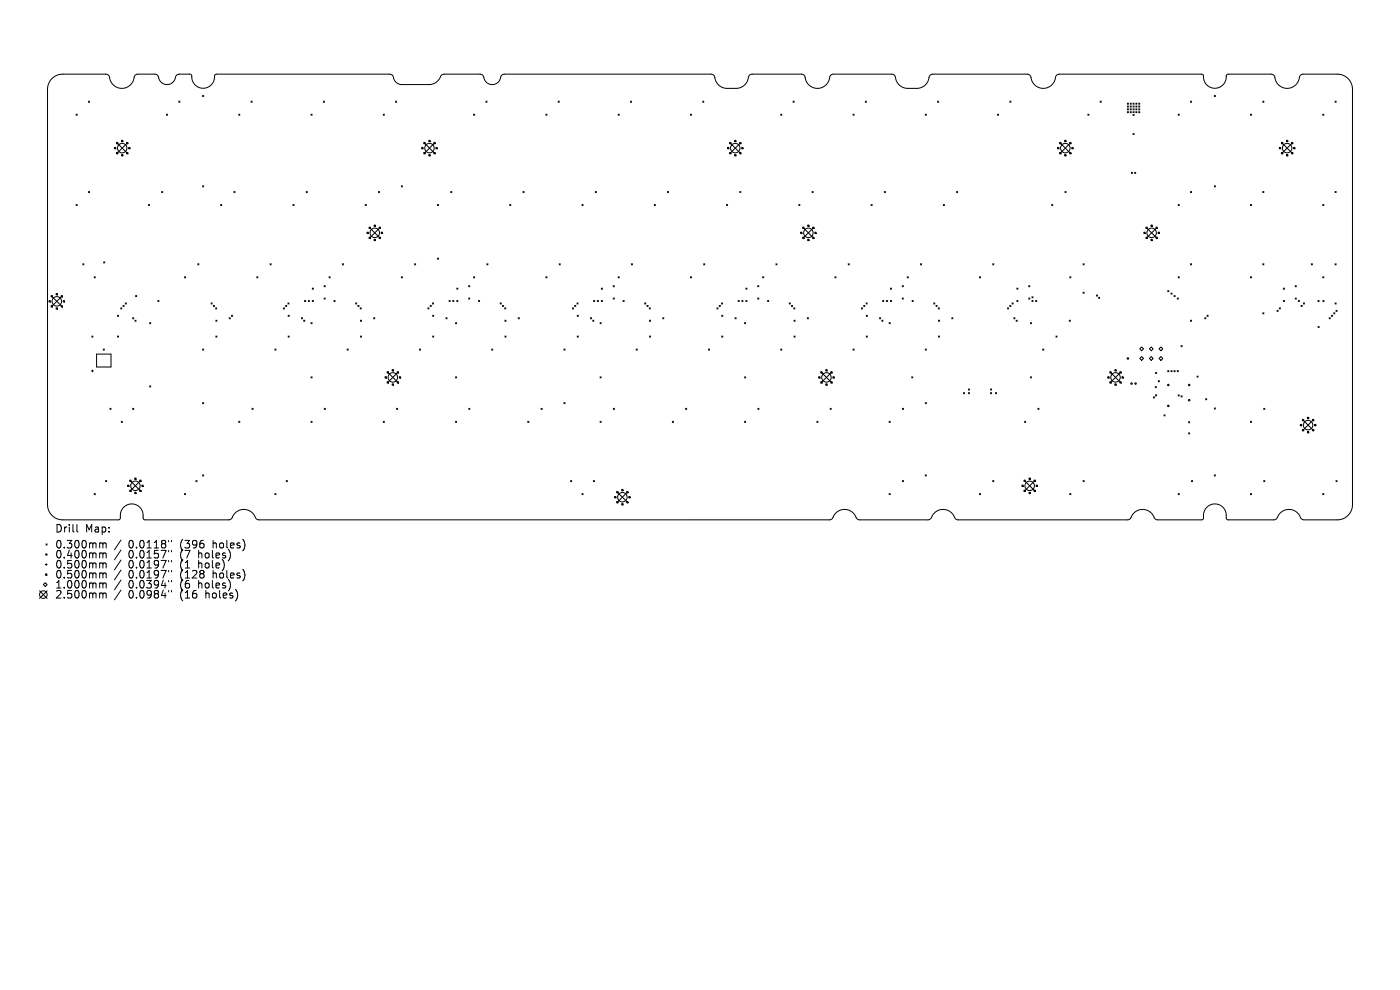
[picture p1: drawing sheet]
<svg xmlns="http://www.w3.org/2000/svg" width="297mm" height="210mm" viewBox="0 0 297 210" stroke-linecap="round" stroke-linejoin="round" font-family="sans-serif">
<defs><g id="words">
<g font-size="2.2">
<text x="11.6" y="113.2">Drill</text>
<text x="18.1" y="113.2">Map:</text>
<text x="11.6" y="116.6">0.300mm</text>
<text x="11.6" y="118.7">0.400mm</text>
<text x="27.3" y="116.6">0.0118&quot;</text>
<text x="27.3" y="118.7">0.0157&quot;</text>
<text x="38.3" y="116.6">(396</text>
<text x="38.3" y="118.7">(7</text>
<text x="42.3" y="118.7">holes)</text>
<text x="45.4" y="116.6">holes)</text>
<text x="11.6" y="120.8">0.500mm</text>
<text x="11.6" y="122.9">0.500mm</text>
<text x="11.6" y="125.1">1.000mm</text>
<text x="27.3" y="120.8">0.0197&quot;</text>
<text x="27.3" y="122.9">0.0197&quot;</text>
<text x="27.3" y="125.1">0.0394&quot;</text>
<text x="38.3" y="120.8">(1</text>
<text x="38.3" y="122.9">(128</text>
<text x="38.3" y="125.1">(6</text>
<text x="42.3" y="120.8">hole)</text>
<text x="42.3" y="125.1">holes)</text>
<text x="45.4" y="122.9">holes)</text>
<text x="11.6" y="127.2">2.500mm</text>
<text x="27.3" y="127.2">0.0984&quot;</text>
<text x="38.3" y="127.2">(16</text>
<text x="43.8" y="127.2">holes)</text>
</g>
</g></defs>
<g fill="none" stroke="#000" stroke-width=".21">
<path d="M11.1 16.6a3.2 3.2 0 0 1 2.3-.9h9.1a.81 .81 0 0 1 .8 .7 2.66 2.66 0 0 0 2.7 2.3 2.66 2.66 0 0 0 2.5-2.6l.7-.4h3.7a1.03 1.03 0 0 1 .9 1.2 1.89 1.89 0 0 0 2.1 1 1.89 1.89 0 0 0 1.5-1.8l.6-.4h2.3l.3 .2a2.5 2.5 0 0 0 2.5 2.8 2.5 2.5 0 0 0 2.5-2.8l.3-.2h36.8a1.03 1.03 0 0 1 .9 1.2l.6 .7 .9 .3h6.1a3.5 3.5 0 0 0 2.6-2l.4-.2h7.6a1.03 1.03 0 0 1 1 1.2 1.88 1.88 0 0 0 2.1 1 1.88 1.88 0 0 0 1.4-1.8l.7-.4h43.8a.81 .81 0 0 1 .8 .7 2.62 2.62 0 0 0 2.6 2.3h2.2a2.94 2.94 0 0 0 2.5-2.6l.7-.4h10.4a.8 .8 0 0 1 .8 .7 2.66 2.66 0 0 0 2.8 2.3 2.66 2.66 0 0 0 2.5-2.6l.3-.3 .4-.1h12.4a.8 .8 0 0 1 .8 .7 2.62 2.62 0 0 0 2.6 2.3h2.1a2.94 2.94 0 0 0 2.5-2.6l.7-.4h20a.8 .8 0 0 1 .8 .7 2.66 2.66 0 0 0 2.8 2.3 2.66 2.66 0 0 0 2.5-2.6l.3-.3 .4-.1h30.2l.4 .2a2.5 2.5 0 0 0 2.5 2.8 2.5 2.5 0 0 0 2.4-2.8l.3-.2h9.2a.81 .81 0 0 1 .8 .7 2.67 2.67 0 0 0 2.8 2.3 2.67 2.67 0 0 0 2.5-2.6l.6-.4h7.3a3.2 3.2 0 0 1 3.2 3.2v88.2a3.2 3.2 0 0 1-3.2 3.2h-7.1l-.5-.3a2.74 2.74 0 0 0-2.7-1.9 2.74 2.74 0 0 0-2.6 1.9l-.6 .3h-9.7l-.2-.1-.2-.3a2.48 2.48 0 0 0-3-2.9 2.53 2.53 0 0 0-1.8 2.9l-.1 .3-.3 .1h-9.3l-.6-.3a2.74 2.74 0 0 0-2.6-1.9 2.74 2.74 0 0 0-2.6 1.9l-.6 .3h-35.9l-.6-.2a2.86 2.86 0 0 0-3.8-1.8l-.9 .7-.6 1-.5 .3h-14.5l-.5-.2a2.86 2.86 0 0 0-3.9-1.8l-.9 .7-.6 1-.5 .3h-121.1l-.5-.2a2.86 2.86 0 0 0-3.8-1.8l-.9 .7-.6 1-.5 .3h-17.8l-.3-.1-.1-.3a2.48 2.48 0 0 0-3.1-2.9 2.53 2.53 0 0 0-1.8 2.9l-.1 .3-.3 .1h-11.8a3.2 3.2 0 0 1-3.2-3.2v-88.2a3.2 3.2 0 0 1 1-2.3zM16.1 24.2l.3 .3M16.4 24.2l-.3 .3M18.8 21.5l.2 .2M19 21.5l-.2 .2M24.3 31.3h.3v.3h-.3zM24.7 30.2h.3v.3h-.3zM24.7 32.3h.3v.3h-.3zM24.9 30.4l2 2M25.8 29.8h.3v.3h-.3zM25.8 32.8h.3v.3h-.3zM26.8 30.2h.3v.3h-.3z"/>
<path d="M26.8 32.3h.3v.3h-.3zM26.9 30.4l-2 2M27.3 31.3h.3v.3h-.3zM35.3 24.2l.3 .3M35.6 24.2l-.3 .3M37.9 21.5l.3 .2M38.2 21.5l-.3 .2M43 20.2l.2 .3M43 39.4l.2 .3M43.2 20.2l-.2 .3M43.2 39.4l-.2 .3M50.6 24.2l.3 .3"/>
<path d="M50.9 24.2l-.3 .3M53.3 21.5l.2 .2M53.5 21.5l-.2 .2M66 24.2l.2 .3M66.2 24.2l-.2 .3M68.6 21.5l.2 .2M68.8 21.5l-.2 .2M81.3 24.2l.2 .3M81.5 24.2l-.2 .3M83.9 21.5l.3 .2M84.2 21.5l-.3 .2M85.1 39.4l.3 .3"/>
<path d="M85.4 39.4l-.3 .3M89.5 31.3h.2v.3h-.2zM89.9 30.2h.3v.3h-.3zM89.9 32.3h.3v.3h-.3zM90.1 30.4l2 2M91 29.8h.3v.3h-.3zM91 32.8h.3v.3h-.3zM92 30.2h.3v.3h-.3zM92 32.3h.3v.3h-.3zM92.1 30.4l-2 2M92.5 31.3h.3v.3h-.3zM100.5 24.2l.2 .3"/>
<path d="M100.7 24.2l-.2 .3M103.1 21.5l.2 .2M103.3 21.5l-.2 .2M115.8 24.2l.2 .3M116 24.2l-.2 .3M118.4 21.5l.3 .2M118.7 21.5l-.3 .2M131.1 24.2l.3 .3M131.4 24.2l-.3 .3M133.7 21.5l.3 .2M134 21.5l-.3 .2M146.5 24.2l.2 .3"/>
<path d="M146.7 24.2l-.2 .3M149.1 21.5l.2 .2M149.3 21.5l-.2 .2M154.3 31.3h.3v.3h-.3zM154.8 30.2h.3v.3h-.3zM154.8 32.3h.3v.3h-.3zM155 30.4l2 2M155.8 29.8h.3v.3h-.3zM155.8 32.8h.3v.3h-.3zM156.9 30.2h.3v.3h-.3zM156.9 32.3h.3v.3h-.3zM157 30.4l-2 2"/>
<path d="M157.4 31.3h.2v.3h-.2zM165.6 24.2l.3 .3M165.9 24.2l-.3 .3M168.2 21.5l.3 .2M168.5 21.5l-.3 .2M181 24.2l.2 .3M181.2 24.2l-.2 .3M183.6 21.5l.2 .2M183.8 21.5l-.2 .2M196.3 24.2l.2 .3M196.5 24.2l-.2 .3M198.9 21.5l.2 .2"/>
<path d="M199.1 21.5l-.2 .2M211.6 24.2l.3 .3M211.9 24.2l-.3 .3M214.2 21.5l.3 .2M214.5 21.5l-.3 .2M224.3 31.3h.3v.3h-.3zM224.8 30.2h.3v.3h-.3zM224.8 32.3h.3v.3h-.3zM225 30.4l2 2M225.9 29.8h.2v.3h-.2zM225.9 32.8h.2v.3h-.2zM226.9 30.2h.3v.3h-.3z"/>
<path d="M226.9 32.3h.3v.3h-.3zM227 30.4l-2 2M227.4 31.3h.3v.3h-.3zM230.8 24.2l.2 .3M231 24.2l-.2 .3M233.4 21.5l.2 .2M233.6 21.5l-.2 .2M239.2 21.9l.2 .2M239.2 22.5l.2 .2M239.2 23.1l.2 .2M239.2 23.7l.2 .2M239.4 21.9l-.2 .2"/>
<path d="M239.4 22.5l-.2 .2M239.4 23.1l-.2 .2M239.4 23.7l-.2 .2M239.8 22.5l.2 .2M239.8 23.1l.2 .2M239.8 23.7l.2 .2M239.8 21.9l.2 .2M240 21.9l-.2 .2M240 22.5l-.2 .2M240 23.1l-.2 .2M240 23.7l-.2 .2M240 36.5l.3 .3"/>
<path d="M240.3 36.5l-.3 .3M240.4 23.1l.2 .2M240.4 23.7l.2 .2M240.4 24.3l.2 .2M240.4 22.5l.2 .2M240.4 21.9l.2 .2M240.4 28.3l.2 .3M240.6 21.9l-.2 .2M240.6 22.5l-.2 .2M240.6 23.1l-.2 .2M240.6 23.7l-.2 .2M240.6 24.3l-.2 .2"/>
<path d="M240.6 28.3l-.2 .3M240.7 36.5l.2 .3M240.9 36.5l-.2 .3M241 23.7l.2 .2M241 23.1l.2 .2M241 22.5l.2 .2M241 21.9l.2 .2M241.2 21.9l-.2 .2M241.2 22.5l-.2 .2M241.2 23.1l-.2 .2M241.2 23.7l-.2 .2M241.6 23.7l.2 .2"/>
<path d="M241.6 23.1l.2 .2M241.6 22.5l.2 .2M241.6 21.9l.2 .2M241.8 21.9l-.2 .2M241.8 22.5l-.2 .2M241.8 23.1l-.2 .2M241.8 23.7l-.2 .2M249.9 24.2l.3 .3M250.2 24.2l-.3 .3M252.6 21.5l.2 .2M252.8 21.5l-.2 .2M257.6 20.2l.2 .3"/>
<path d="M257.6 39.4l.2 .3M257.8 20.2l-.2 .3M257.8 39.4l-.2 .3M265.3 24.2l.2 .3M265.5 24.2l-.2 .3M267.9 21.5l.2 .2M268.1 21.5l-.2 .2M271.4 31.3h.3v.3h-.3zM271.8 30.2h.3v.3h-.3zM271.8 32.3h.3v.3h-.3zM272.1 30.4l2 2M272.9 29.8h.3v.3h-.3z"/>
<path d="M272.9 32.8h.3v.3h-.3zM274 30.2h.3v.3h-.3zM274 32.3h.3v.3h-.3zM274.1 30.4l-2 2M274.4 31.3h.3v.3h-.3zM280.6 24.2l.2 .3M280.8 24.2l-.2 .3M283.2 21.5l.3 .2M283.5 21.5l-.3 .2M16.1 43.4l.3 .2M16.4 43.4l-.3 .2M17.6 56l.2 .2"/>
<path d="M17.8 56l-.2 .2M18.8 40.6l.2 .3M19 40.6l-.2 .3M20 58.7l.2 .2M20.2 58.7l-.2 .2M22 55.5l.2 .3M22.2 55.5l-.2 .3M31.5 43.4l.2 .2M31.7 43.4l-.2 .2M34.3 40.6l.2 .3M34.5 40.6l-.2 .3M39.1 58.7l.3 .2"/>
<path d="M39.4 58.7l-.3 .2M42 56l.2 .2M42.2 56l-.2 .2M46.8 43.4l.2 .2M47 43.4l-.2 .2M49.6 40.6l.3 .3M49.9 40.6l-.3 .3M54.5 58.7l.2 .2M54.7 58.7l-.2 .2M57.3 56l.2 .2M57.5 56l-.2 .2M62.1 43.4l.3 .2"/>
<path d="M62.4 43.4l-.3 .2M65 40.6l.2 .3M65.2 40.6l-.2 .3M69.8 58.7l.2 .2M70 58.7l-.2 .2M72.6 56l.3 .2M72.9 56l-.3 .2M77.5 43.4l.2 .2M77.7 43.4l-.2 .2M77.9 49.3h.2v.2h-.2zM78.3 48.2h.3v.3h-.3zM78.3 50.3h.3v.3h-.3z"/>
<path d="M78.5 48.4l2 2M79.4 47.7h.2v.3h-.2zM79.4 50.8h.2v.2h-.2zM80.3 40.6l.2 .3M80.4 48.2h.3v.3h-.3zM80.4 50.3h.3v.3h-.3zM80.5 48.4l-2 2M80.5 40.6l-.2 .3M80.9 49.3h.3v.2h-.3zM85.1 58.7l.3 .2M85.4 58.7l-.3 .2M88 56l.2 .2"/>
<path d="M88.2 56l-.2 .2M92.8 43.4l.2 .2M92.8 54.7l.2 .3M93 43.4l-.2 .2M93 54.7l-.2 .3M95.6 40.6l.3 .3M95.9 40.6l-.3 .3M100.5 58.7l.2 .2M100.7 58.7l-.2 .2M103.3 56l.2 .2M103.5 56l-.2 .2M108.1 43.4l.3 .2"/>
<path d="M108.4 43.4l-.3 .2M110.9 40.6l.3 .3M111.2 40.6l-.3 .3M115.8 58.7l.2 .2M116 58.7l-.2 .2M118.6 56l.3 .2M118.9 56l-.3 .2M123.5 43.4l.2 .2M123.7 43.4l-.2 .2M126.3 40.6l.2 .3M126.5 40.6l-.2 .3M131.1 58.7l.3 .2"/>
<path d="M131.4 58.7l-.3 .2M133.9 56l.3 .2M134.2 56l-.3 .2M138.8 43.4l.2 .2M139 43.4l-.2 .2M141.6 40.6l.3 .3M141.9 40.6l-.3 .3M146.5 58.7l.2 .2M146.7 58.7l-.2 .2M149.3 56l.2 .2M149.5 56l-.2 .2M154.1 43.4l.3 .2"/>
<path d="M154.4 43.4l-.3 .2M156.9 40.6l.3 .3M157.2 40.6l-.3 .3M161.8 58.7l.2 .2M162 58.7l-.2 .2M164.6 56l.2 .2M164.8 56l-.2 .2M169.5 43.4l.2 .2M169.7 43.4l-.2 .2M169.8 49.3h.3v.2h-.3zM170.3 48.2h.3v.3h-.3zM170.3 50.3h.3v.3h-.3z"/>
<path d="M170.5 48.4l2 2M171.3 47.7h.3v.3h-.3zM171.3 50.8h.3v.2h-.3zM172.3 40.6l.2 .3M172.4 48.2h.3v.3h-.3zM172.4 50.3h.3v.3h-.3zM172.5 48.4l-2 2M172.5 40.6l-.2 .3M172.9 49.3h.2v.2h-.2zM177.1 58.7l.3 .2M177.4 58.7l-.3 .2M179.9 56l.3 .2"/>
<path d="M180.2 56l-.3 .2M184.8 43.4l.2 .2M185 43.4l-.2 .2M187.6 40.6l.2 .3M187.8 40.6l-.2 .3M192.5 58.7l.2 .2M192.7 58.7l-.2 .2M195.3 56l.2 .2M195.5 56l-.2 .2M200.1 43.4l.3 .2M200.4 43.4l-.3 .2M202.9 40.6l.3 .3"/>
<path d="M203.2 40.6l-.3 .3M207.8 58.7l.2 .2M208 58.7l-.2 .2M210.6 56l.2 .2M210.8 56l-.2 .2M223.1 43.4l.3 .2M223.4 43.4l-.3 .2M225.9 40.6l.3 .3M226.2 40.6l-.3 .3M226.9 58.7l.3 .2M227.2 58.7l-.3 .2M229.8 56l.2 .2"/>
<path d="M230 56l-.2 .2M242.7 49.3h.2v.2h-.2zM243.1 48.2h.3v.3h-.3zM243.1 50.3h.3v.3h-.3zM243.3 48.4l2 2M244.2 47.7h.3v.3h-.3zM244.2 50.8h.3v.2h-.3zM245.2 48.2h.3v.3h-.3zM245.2 50.3h.3v.3h-.3zM245.3 48.4l-2 2M245.7 49.3h.3v.2h-.3zM249.9 43.4l.3 .2"/>
<path d="M249.9 58.7l.3 .2M250.2 43.4l-.3 .2M250.2 58.7l-.3 .2M252.6 40.6l.2 .3M252.6 56l.2 .2M252.8 40.6l-.2 .3M252.8 56l-.2 .2M265.3 43.4l.2 .2M265.3 58.7l.2 .2M265.5 43.4l-.2 .2M265.5 58.7l-.2 .2M267.9 56l.2 .2"/>
<path d="M267.9 40.6l.2 .3M268.1 56l-.2 .2M268.1 40.6l-.2 .3M278.2 56l.2 .2M278.4 56l-.2 .2M280.6 43.4l.2 .2M280.6 58.7l.2 .2M280.8 43.4l-.2 .2M280.8 58.7l-.2 .2M283.2 56l.3 .2M283.2 40.6l.3 .3M283.5 40.6l-.3 .3"/>
<path d="M283.5 56l-.3 .2M10.4 63.8h.3v.3h-.3zM10.8 62.7h.3v.3h-.3zM10.8 64.8h.3v.3h-.3zM11 62.9l2.1 2M11.9 62.3h.3v.3h-.3zM11.9 65.3h.3v.3h-.3zM13 62.7h.3v.3h-.3zM13 64.8h.3v.3h-.3zM13.1 62.9l-2.1 2M13.4 63.8h.3v.3h-.3zM19.4 78.7h.4"/>
<path d="M19.5 71.3l.2 .2M19.6 78.5v.4M19.7 71.3l-.2 .2M20.5 75.1h3v2.7h-3zM21.9 74l.2 .3M22.1 74l-.2 .3M24.9 66.9l.3 .2M24.9 71.3l.3 .2M25.2 66.9l-.3 .2M25.2 71.3l-.3 .2M25.6 65.3l.3 .2M25.9 65.3l-.3 .2"/>
<path d="M26.1 64.8l.2 .2M26.3 64.8l-.2 .2M26.6 64.3l.2 .2M26.8 64.3l-.2 .2M28.1 67.4l.3 .2M28.4 67.4l-.3 .2M28.6 67.9l.3 .3M28.8 62.7l.2 .2M28.9 67.9l-.3 .3M29 62.7l-.2 .2M31.7 68.4l.3 .3M32 68.4l-.3 .3"/>
<path d="M33.5 63.7l.2 .3M33.7 63.7l-.2 .3M43 74l.2 .3M43.2 74l-.2 .3M44.8 64.3l.2 .2M45 64.3l-.2 .2M45.3 64.8l.2 .2M45.5 64.8l-.2 .2M45.7 65.3l.3 .2M45.8 67.9l.2 .3M45.8 71.3l.2 .2M46 65.3l-.3 .2"/>
<path d="M46 67.9l-.2 .3M46 71.3l-.2 .2M48.6 67.4l.3 .2M48.9 67.4l-.3 .2M49.1 66.9l.2 .2M49.3 66.9l-.2 .2M58.3 74l.2 .3M58.5 74l-.2 .3M60.1 65.3l.2 .2M60.3 65.3l-.2 .2M60.6 64.8l.2 .2M60.8 64.8l-.2 .2"/>
<path d="M61.1 64.3l.2 .2M61.1 66.9l.3 .2M61.1 71.3l.3 .2M61.3 64.3l-.2 .2M61.4 71.3l-.3 .2M61.4 66.9l-.3 .2M63.9 67.4l.3 .2M64.2 67.4l-.3 .2M64.4 67.9l.3 .3M64.6 63.7l.2 .3M64.7 67.9l-.3 .3M64.8 63.7l-.2 .3"/>
<path d="M65.4 63.7l.2 .3M65.6 63.7l-.2 .3M66 68.4l.2 .3M66 79.9l.2 .3M66.2 68.4l-.2 .3M66.2 79.9l-.2 .3M66.2 61.1l.3 .3M66.2 63.7l.3 .3M66.5 61.1l-.3 .3M66.5 63.7l-.3 .3M68.8 60.6l.2 .2M68.8 63.2l.2 .3"/>
<path d="M69 60.6l-.2 .2M69 63.2l-.2 .3M70.9 63.7l.2 .3M71.1 63.7l-.2 .3M73.6 74l.3 .3M73.9 74l-.3 .3M75.4 64.3l.3 .2M75.7 64.3l-.3 .2M75.9 64.8l.3 .2M76.2 64.8l-.3 .2M76.4 65.3l.2 .2M76.5 71.3l.2 .2"/>
<path d="M76.5 67.9l.2 .3M76.6 65.3l-.2 .2M76.7 67.9l-.2 .3M76.7 71.3l-.2 .2M79.3 67.4l.2 .2M79.5 67.4l-.2 .2M81.7 79.9h.3v.3h-.3zM82.1 78.8h.3v.3h-.3zM82.3 79.1l2 2M83.2 78.4h.3v.3h-.3zM84.3 78.8h.2v.3h-.2zM84.3 79.1l-2 2"/>
<path d="M84.7 79.9h.3v.3h-.3zM89 74l.2 .3M89.2 74l-.2 .3M90.8 65.3l.2 .2M91 65.3l-.2 .2M91.3 64.8l.2 .2M91.5 64.8l-.2 .2M91.7 64.3l.3 .2M91.8 66.9l.2 .2M91.8 71.3l.2 .2M92 64.3l-.3 .2M92 71.3l-.2 .2"/>
<path d="M92 66.9l-.2 .2M94.6 67.4l.2 .2M94.8 67.4l-.2 .2M95.3 63.7l.2 .3M95.5 63.7l-.2 .3M96.1 63.7l.2 .3M96.3 63.7l-.2 .3M96.6 68.4l.3 .3M96.6 79.9l.3 .3M96.9 68.4l-.3 .3M96.9 79.9l-.3 .3M96.9 61.1l.2 .3"/>
<path d="M96.9 63.7l.2 .3M97.1 61.1l-.2 .3M97.1 63.7l-.2 .3M99.4 60.6l.3 .2M99.4 63.2l.3 .3M99.7 63.2l-.3 .3M99.7 60.6l-.3 .2M101.5 63.7l.3 .3M101.8 63.7l-.3 .3M104.3 74l.2 .3M104.5 74l-.2 .3M106.1 64.3l.2 .2"/>
<path d="M106.3 64.3l-.2 .2M106.6 64.8l.2 .2M106.8 64.8l-.2 .2M107.1 65.3l.2 .2M107.1 71.3l.3 .2M107.1 67.9l.3 .3M107.3 65.3l-.2 .2M107.4 67.9l-.3 .3M107.4 71.3l-.3 .2M109.9 67.4l.3 .2M110.2 67.4l-.3 .2M119.6 74l.3 .3"/>
<path d="M119.9 74l-.3 .3M121.4 65.3l.3 .2M121.7 65.3l-.3 .2M121.9 64.8l.3 .2M122.2 64.8l-.3 .2M122.4 64.3l.2 .2M122.4 66.9l.3 .2M122.4 71.3l.3 .2M122.6 64.3l-.2 .2M122.7 66.9l-.3 .2M122.7 71.3l-.3 .2M125.3 67.4l.2 .2"/>
<path d="M125.5 67.4l-.2 .2M125.7 67.9l.3 .3M125.9 63.7l.3 .3M126 67.9l-.3 .3M126.2 63.7l-.3 .3M126.7 63.7l.3 .3M127 63.7l-.3 .3M127.3 79.9l.2 .3M127.3 68.4l.2 .3M127.5 68.4l-.2 .3M127.5 79.9l-.2 .3M127.6 61.1l.2 .3"/>
<path d="M127.6 63.7l.2 .3M127.8 61.1l-.2 .3M127.8 63.7l-.2 .3M130.1 60.6l.2 .2M130.1 63.2l.2 .3M130.3 60.6l-.2 .2M130.3 63.2l-.2 .3M132.2 63.7l.2 .3M132.4 63.7l-.2 .3M135 74l.2 .3M135.2 74l-.2 .3M136.8 64.3l.2 .2"/>
<path d="M137 64.3l-.2 .2M137.2 64.8l.3 .2M137.5 64.8l-.3 .2M137.7 65.3l.3 .2M137.8 67.9l.2 .3M137.8 71.3l.2 .2M138 65.3l-.3 .2M138 67.9l-.2 .3M138 71.3l-.2 .2M140.6 67.4l.2 .2M140.8 67.4l-.2 .2M150.3 74l.2 .3"/>
<path d="M150.5 74l-.2 .3M152.1 65.3l.2 .2M152.3 65.3l-.2 .2M152.6 64.8l.2 .2M152.8 64.8l-.2 .2M153.1 64.3l.2 .2M153.1 66.9l.2 .2M153.1 71.3l.2 .2M153.3 64.3l-.2 .2M153.3 66.9l-.2 .2M153.3 71.3l-.2 .2M155.9 67.4l.3 .2"/>
<path d="M156.2 67.4l-.3 .2M156.6 63.7l.2 .3M156.8 63.7l-.2 .3M157.4 63.7l.2 .3M157.6 63.7l-.2 .3M158 79.9l.2 .3M158 68.4l.2 .3M158.2 68.4l-.2 .3M158.2 79.9l-.2 .3M158.2 61.1l.3 .3M158.2 63.7l.3 .3M158.5 61.1l-.3 .3"/>
<path d="M158.5 63.7l-.3 .3M160.7 60.6l.3 .2M160.7 63.2l.3 .3M161 60.6l-.3 .2M161 63.2l-.3 .3M162.8 63.7l.3 .3M163.1 63.7l-.3 .3M165.6 74l.3 .3M165.9 74l-.3 .3M167.4 64.3l.3 .2M167.7 64.3l-.3 .2M167.9 64.8l.2 .2"/>
<path d="M168.1 64.8l-.2 .2M168.4 65.3l.2 .2M168.4 71.3l.3 .2M168.4 67.9l.3 .3M168.6 65.3l-.2 .2M168.7 67.9l-.3 .3M168.7 71.3l-.3 .2M171.3 67.4l.2 .2M171.5 67.4l-.2 .2M173.7 79.9h.3v.3h-.3zM174.1 78.8h.3v.3h-.3zM174.3 79.1l2 2"/>
<path d="M175.2 78.4h.3v.3h-.3zM176.2 78.8h.3v.3h-.3zM176.3 79.1l-2 2M176.7 79.9h.3v.3h-.3zM181 74l.2 .3M181.2 74l-.2 .3M182.8 65.3l.2 .2M183 65.3l-.2 .2M183.2 64.8l.3 .2M183.5 64.8l-.3 .2M183.7 64.3l.3 .2M183.8 66.9l.2 .2"/>
<path d="M183.8 71.3l.2 .2M184 64.3l-.3 .2M184 66.9l-.2 .2M184 71.3l-.2 .2M186.6 67.4l.2 .2M186.8 67.4l-.2 .2M187.1 67.9l.2 .3M187.3 63.7l.2 .3M187.3 67.9l-.2 .3M187.5 63.7l-.2 .3M188 63.7l.3 .3M188.3 63.7l-.3 .3"/>
<path d="M188.6 68.4l.3 .3M188.9 68.4l-.3 .3M188.9 61.1l.2 .3M188.9 63.7l.2 .3M189.1 61.1l-.2 .3M189.1 63.7l-.2 .3M191.4 60.6l.2 .2M191.4 63.2l.2 .3M191.6 60.6l-.2 .2M191.6 63.2l-.2 .3M193.4 79.9l.3 .3M193.5 63.7l.2 .3"/>
<path d="M193.7 79.9l-.3 .3M193.7 63.7l-.2 .3M196.3 74l.2 .3M196.5 74l-.2 .3M198.1 64.3l.2 .2M198.3 64.3l-.2 .2M198.6 64.8l.2 .2M198.8 64.8l-.2 .2M199.1 65.3l.2 .2M199.1 71.3l.2 .2M199.1 67.9l.2 .3M199.3 65.3l-.2 .2"/>
<path d="M199.3 71.3l-.2 .2M199.3 67.9l-.2 .3M201.9 67.4l.3 .2M202.2 67.4l-.3 .2M213.7 65.3l.3 .2M214 65.3l-.3 .2M214.2 64.8l.3 .2M214.5 64.8l-.3 .2M214.7 64.3l.2 .2M214.9 64.3l-.2 .2M215.1 67.4l.2 .2M215.3 67.4l-.2 .2"/>
<path d="M215.6 67.9l.2 .3M215.7 61.1l.3 .3M215.7 63.7l.3 .3M215.8 67.9l-.2 .3M216 61.1l-.3 .3M216 63.7l-.3 .3M218.2 60.6l.3 .2M218.2 63.2l.3 .3M218.5 60.6l-.3 .2M218.5 63.2l-.3 .3M218.6 68.4l.2 .3M218.6 79.9l.2 .3"/>
<path d="M218.8 68.4l-.2 .3M218.8 79.9l-.2 .3M218.9 62.9l.3 .3M218.9 63.7l.3 .3M219.2 62.9l-.3 .3M219.2 63.7l-.3 .3M219.7 63.7l.2 .3M219.9 63.7l-.2 .3M221.2 74l.2 .3M221.4 74l-.2 .3M224 71.3l.3 .2M224.3 71.3l-.3 .2"/>
<path d="M226.8 67.9l.3 .3M227.1 67.9l-.3 .3M229.8 62l.2 .2M230 62l-.2 .2M232.6 62.6l.2 .2M232.8 62.6l-.2 .2M233.1 63.1l.2 .2M233.3 63.1l-.2 .2M235 79.9h.3v.3h-.3zM235.4 78.8h.3v.3h-.3zM235.6 79.1l2.1 2M236.5 78.4h.3v.3h-.3z"/>
<path d="M237.6 78.8h.3v.3h-.3zM237.7 79.1l-2.1 2M238 79.9h.3v.3h-.3zM241.8 74l.4-.4 .4 .4-.4 .4zM242.2 75.6l.4 .4-.4 .4-.4-.4zM244.2 73.6l.4 .4-.4 .4-.4-.4zM244.2 75.6l.4 .4-.4 .4-.4-.4zM245.1 79l.3 .2M245.4 79l-.3 .2M245.9 74l.4-.4 .4 .4-.4 .4zM245.9 76l.4-.4 .4 .4-.4 .4zM247.7 61.6l.3 .3"/>
<path d="M247.7 78.6l.3 .3M248 61.6l-.3 .3M248 78.6l-.3 .3M248.4 62.2l.3 .2M248.4 78.6l.3 .3M248.7 78.6l-.3 .3M248.7 62.2l-.3 .2M249.1 62.7l.2 .2M249.1 78.6l.2 .3M249.3 62.7l-.2 .2M249.3 78.6l-.2 .3M249.7 63.2l.3 .3"/>
<path d="M249.7 78.6l.3 .3M250 63.2l-.3 .3M250 78.6l-.3 .3M250.5 73.3l.3 .2M250.8 73.3l-.3 .2M252.6 67.9l.2 .3M252.8 67.9l-.2 .3M253.9 79.8l.3 .2M254.2 79.8l-.3 .2M255.6 67.4l.2 .2M255.8 67.4l-.2 .2M256.1 66.9l.2 .2"/>
<path d="M256.3 66.9l-.2 .2M267.9 66.3l.2 .3M268.1 66.3l-.2 .3M270.9 65.8l.2 .3M271.1 65.8l-.2 .3M271.4 65.3l.2 .2M271.6 65.3l-.2 .2M272.3 61.1l.2 .3M272.3 63.7l.2 .3M272.5 61.1l-.2 .3M272.5 63.7l-.2 .3M274.8 60.6l.2 .2"/>
<path d="M274.8 63.2l.2 .3M275 60.6l-.2 .2M275 63.2l-.2 .3M275.4 63.7l.3 .3M275.7 63.7l-.3 .3M276 64.8l.3 .2M276.3 64.8l-.3 .2M276.5 64.3l.2 .2M276.7 64.3l-.2 .2M279.6 63.7l.2 .3M279.6 69.2l.3 .3M279.8 63.7l-.2 .3"/>
<path d="M279.9 69.2l-.3 .3M280.6 63.7l.3 .3M280.9 63.7l-.3 .3M282 67.4l.2 .2M282.2 67.4l-.2 .2M282.5 66.9l.2 .2M282.7 66.9l-.2 .2M282.9 66.3l.3 .3M283.2 66.3l-.3 .3M283.2 64.3l.3 .2M283.4 65.8l.3 .3M283.5 64.3l-.3 .2"/>
<path d="M283.7 65.8l-.3 .3M23.3 86.6l.3 .3M23.6 86.6l-.3 .3M25.7 89.4l.3 .2M26 89.4l-.3 .2M28.1 86.6l.3 .3M28.4 86.6l-.3 .3M31.7 81.9l.3 .2M32 81.9l-.3 .2M43 85.4l.2 .2M43.2 85.4l-.2 .2M50.6 89.4l.3 .2"/>
<path d="M50.9 89.4l-.3 .2M53.5 86.6l.2 .3M53.7 86.6l-.2 .3M66 89.4l.2 .2M66.2 89.4l-.2 .2M68.8 86.6l.2 .3M69 86.6l-.2 .3M81.3 89.4l.2 .2M81.5 89.4l-.2 .2M82.1 81h.3v.3h-.3zM83.2 81.4h.3v.3h-.3zM84.1 86.6l.3 .3"/>
<path d="M84.3 81h.2v.3h-.2zM84.4 86.6l-.3 .3M96.6 89.4l.3 .2M96.9 89.4l-.3 .2M99.5 86.6l.2 .3M99.7 86.6l-.2 .3M112 89.4l.2 .2M112.2 89.4l-.2 .2M114.8 86.6l.2 .3M115 86.6l-.2 .3M119.6 85.4l.3 .2M119.9 85.4l-.3 .2"/>
<path d="M127.3 89.4l.2 .2M127.5 89.4l-.2 .2M130.1 86.6l.3 .3M130.4 86.6l-.3 .3M142.6 89.4l.3 .2M142.9 89.4l-.3 .2M145.4 86.6l.3 .3M145.7 86.6l-.3 .3M158 89.4l.2 .2M158.2 89.4l-.2 .2M160.8 86.6l.2 .3M161 86.6l-.2 .3"/>
<path d="M173.3 89.4l.2 .2M173.5 89.4l-.2 .2M174.1 81h.3v.3h-.3zM175.2 81.4h.3v.3h-.3zM176.1 86.6l.2 .3M176.2 81h.3v.3h-.3zM176.3 86.6l-.2 .3M188.6 89.4l.3 .2M188.9 89.4l-.3 .2M191.4 86.6l.3 .3M191.7 86.6l-.3 .3M196.3 85.4l.2 .2"/>
<path d="M196.5 85.4l-.2 .2M204.4 83.3l.2 .2M204.6 83.3l-.2 .2M205.4 82.5l.3 .2M205.4 83.3l.3 .2M205.7 82.5l-.3 .2M205.7 83.3l-.3 .2M210.1 82.5l.3 .2M210.1 83.3l.3 .2M210.4 82.5l-.3 .2M210.4 83.3l-.3 .2M211.2 83.3l.2 .2"/>
<path d="M211.4 83.3l-.2 .2M217.4 89.4l.2 .2M217.6 89.4l-.2 .2M220.2 86.6l.2 .3M220.4 86.6l-.2 .3M235.4 81h.3v.3h-.3zM236.5 81.4h.3v.3h-.3zM237.6 81h.3v.3h-.3zM244.7 84.2l.2 .2M244.9 84.2l-.2 .2M245.1 82l.2 .2M245.1 83.7l.3 .3"/>
<path d="M245.3 82l-.2 .2M245.4 83.7l-.3 .3M245.7 80.8l.3 .2M246 80.8l-.3 .2M246.9 88l.3 .2M247.2 88l-.3 .2M249.9 83.8l.3 .2M250.2 83.8l-.3 .2M250.5 84l.3 .2M250.8 84l-.3 .2M252.1 91.8l.3 .3M252.2 89.5l.2 .2"/>
<path d="M252.4 91.8l-.3 .3M252.4 89.5l-.2 .2M255.8 84.6l.2 .2M256 84.6l-.2 .2M257.6 86.5l.2 .3M257.8 86.5l-.2 .3M265.3 89.4l.2 .2M265.5 89.4l-.2 .2M268.1 86.6l.2 .3M268.3 86.6l-.2 .3M275.9 90h.2v.3h-.2zM276.3 89h.3v.3h-.3z"/>
<path d="M276.3 91.1h.3v.3h-.3zM276.5 89.2l2 2M277.4 88.5h.2v.3h-.2zM277.4 91.5h.2v.3h-.2zM278.4 89h.3v.3h-.3zM278.4 91.1h.3v.3h-.3zM278.5 89.2l-2 2M278.9 90h.3v.3h-.3zM9.6 119.8h.4M9.8 115.4l.2 .2M9.8 119.6v.4M10 115.4l-.2 .2"/>
<path d="M16.3 111.3v1.3l.2 .3M20 104.7l.2 .2M20.2 104.7l-.2 .2M21.4 115.2l.4 .2M21.4 117.3l.4 .2M21.4 119.4l.4 .2M21.8 115.4l.3-.2h.3l.1 1M21.8 115.4v.8M21.8 117.5v.9M21.8 119.6v.9M21.8 117.5l.3-.2 .3 .1 .1 1M21.8 119.6l.3-.2 .3 .1 .1 1"/>
<path d="M22.4 101.9l.2 .3M22.6 101.9l-.2 .3M25.7 114.6l-1.4 2M25.7 116.7l-1.4 2.1M25.7 118.8l-1.4 2.1M27.1 102.9h.3v.3h-.3zM27.5 101.8h.3v.3h-.3zM27.5 104h.3v.3h-.3zM27.7 102l2 2.1M28.6 101.4h.3v.3h-.3zM28.6 104.4h.3v.3h-.3zM29.6 101.8h.3v.3h-.3z"/>
<path d="M29.6 104h.3v.3h-.3zM29.7 102l-2 2.1M30.1 102.9h.3v.3h-.3zM35.8 114.6v.3M35.8 116.8v.3M35.8 118.9v.3M36.4 114.6v.3M36.4 116.8v.3M36.4 118.9v.3M39.1 104.7l.3 .2M39.4 104.7l-.3 .2M41.6 101.9l.2 .3"/>
<path d="M41.8 101.9l-.2 .3M43 100.7l.2 .3M43.2 100.7l-.2 .3M58.3 104.7l.2 .2M58.5 104.7l-.2 .2M60.7 101.9l.3 .3M61 101.9l-.3 .3M121 101.9l.3 .3M121.3 101.9l-.3 .3M123.5 104.7l.2 .2M123.7 104.7l-.2 .2M125.9 101.9l.2 .3"/>
<path d="M126.1 101.9l-.2 .3M130.4 105.3h.3v.3h-.3zM130.8 104.3h.3v.2h-.3zM130.8 106.4h.3v.3h-.3zM131 104.5l2 2M131.9 103.8h.3v.3h-.3zM131.9 106.8h.3v.3h-.3zM133 104.3h.2v.2h-.2zM133 106.4h.2v.3h-.2zM133 104.5l-2 2M133.4 105.3h.3v.3h-.3zM188.6 104.7l.3 .2"/>
<path d="M188.9 104.7l-.3 .2M191.4 101.9l.3 .3M191.7 101.9l-.3 .3M196.3 100.7l.2 .3M196.5 100.7l-.2 .3M207.8 104.7l.2 .2M208 104.7l-.2 .2M210.6 101.9l.2 .3M210.8 101.9l-.2 .3M216.8 102.9h.3v.3h-.3zM217.2 101.8h.3v.3h-.3zM217.2 104h.3v.3h-.3z"/>
<path d="M217.4 102l2 2.1M218.3 101.4h.3v.3h-.3zM218.3 104.4h.3v.3h-.3zM219.4 101.8h.3v.3h-.3zM219.4 104h.3v.3h-.3zM219.4 102l-2 2.1M219.8 102.9h.3v.3h-.3zM226.9 104.7l.3 .2M227.2 104.7l-.3 .2M229.8 101.9l.2 .3M230 101.9l-.2 .3M249.9 104.7l.3 .2"/>
<path d="M250.2 104.7l-.3 .2M252.8 101.9l.2 .3M253 101.9l-.2 .3M257.6 100.7l.2 .3M257.8 100.7l-.2 .3M265.3 104.7l.2 .2M265.5 104.7l-.2 .2M268.1 101.9l.2 .3M268.3 101.9l-.2 .3M280.6 104.7l.2 .2M280.8 104.7l-.2 .2M283.4 101.9l.3 .3"/>
<path d="M283.7 101.9l-.3 .3M8.4 125.3l1.6 1.6M9.6 123.6l.4 .4-.4 .4-.4-.4zM9.7 121.7h.2v.3h-.2zM10 125.3l-1.6 1.6M21.4 121.5l.4 .3M21.4 123.7l.4 .2M21.4 125.8l.4 .2M21.8 121.8v.8M21.8 123.9v.8M21.8 126v.9M21.8 121.8l.3-.3 .3 .1 .1 1"/>
<path d="M21.8 123.9l.3-.2h.3l.1 1M21.8 126l.3-.2 .3 .1 .1 1M25.7 120.9l-1.4 2.1M25.7 123.1l-1.4 2M25.7 125.2l-1.4 2M35.8 121v.3M35.8 123.1v.3M35.8 125.3v.3M36.4 121v.3M36.4 123.1v.3M36.4 125.3v.3"/>
<circle cx="25.9" cy="31.4" r="1.01"/>
<circle cx="91.1" cy="31.4" r="1.01"/>
<circle cx="156" cy="31.4" r="1.01"/>
<circle cx="226" cy="31.4" r="1.01"/>
<circle cx="273.1" cy="31.4" r="1.01"/>
<circle cx="79.5" cy="49.4" r="1.01"/>
<circle cx="171.5" cy="49.4" r="1.01"/>
<circle cx="244.3" cy="49.4" r="1.01"/>
<circle cx="12.1" cy="63.9" r="1.01"/>
<circle cx="239.3" cy="76" r=".16"/>
<circle cx="83.3" cy="80.1" r="1.01"/>
<circle cx="175.3" cy="80.1" r="1.01"/>
<circle cx="236.6" cy="80.1" r="1.01"/>
<circle cx="240.1" cy="81.4" r=".16"/>
<circle cx="240.9" cy="81.4" r=".16"/>
<circle cx="247.8" cy="86.1" r=".16"/>
<circle cx="247.8" cy="81.7" r=".16"/>
<circle cx="252.3" cy="81.7" r=".16"/>
<circle cx="252.3" cy="84.9" r=".16"/>
<circle cx="277.5" cy="90.2" r="1.01"/>
<circle cx="9.8" cy="117.6" r=".16"/>
<circle cx="28.7" cy="103.1" r="1.01"/>
<circle cx="132" cy="105.5" r="1.01"/>
<circle cx="218.4" cy="103.1" r="1.01"/>
<circle cx="9.2" cy="126.1" r=".8"/>
</g>
<use href="#words"/>
</svg>
